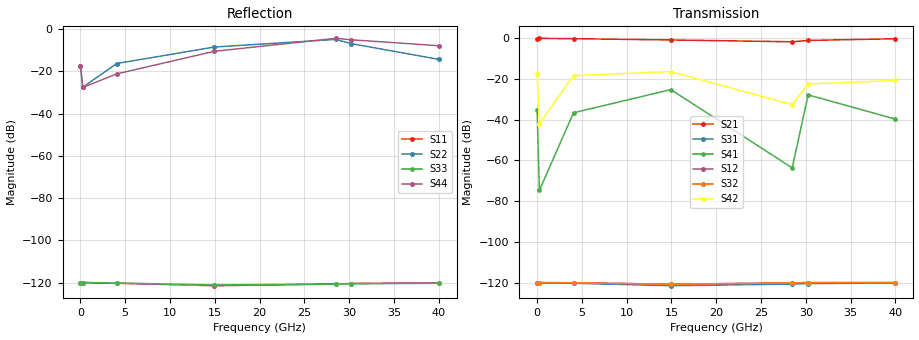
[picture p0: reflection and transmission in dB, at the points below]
# GHz S MA R 50
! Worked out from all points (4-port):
!   4000 points, 5 MHz to 39.99 GHz, reference 50 ohm
!   strongest paths, dB at 5 MHz, 10.01 GHz, 20 GHz, 30 GHz, 39.99 GHz:
!     S21: -0.2, -0.6, -1.2, -1.1, -0.2
!     S43: -0.2, -0.4, -1.1, -1.7, -0.8
!     S42: -17.7, -13.4, -25.6, -24.6, -20.7
!     S23: -35.3, -26.2, -31.6, -28.9, -39.7
!     S41: -35.3, -26.2, -31.6, -28.9, -39.7
!     S32: -120.0, -120.6, -120.7, -119.9, -120.0
!   lowest |S11| = -121.5 dB at 14.93 GHz (marker M1), VSWR 1.00, Z = 50 - j3.09e-06 ohm
!   |S11| at or under -10 dB: start of sweep to end of sweep
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0.005  9.717e-07 0.5  1.002e-06 -0.4  9.718e-07 0.5  1.002e-06 -0.4
       0.9823 0.0  0.1336 124.6  0.01708 179.9  0.1303 110.6
       9.717e-07 0.5  1.002e-06 -0.4  9.718e-07 0.5  1.002e-06 -0.4
       0.01708 -179.9  0.1299 110.2  0.9824 -0.0  0.1328 125.2
0.255  9.99e-07 0.0  1e-06 -0.0  9.99e-07 0.0  1e-06 -0.0
       0.9991 0.0  0.04194 162.0  0.0001843 177.1  0.008002 108.5
       9.99e-07 0.0  1e-06 -0.0  9.99e-07 0.0  1e-06 -0.0
       0.0001843 -177.1  0.008042 109.2  0.9991 -0.0  0.04138 168.8
4.065  9.634e-07 0.4  9.936e-07 -0.4  9.722e-07 0.3  9.952e-07 -0.3
       0.9805 0.0  0.1527 55.9  0.01485 178.3  0.1224 60.4
       9.634e-07 0.4  9.936e-07 -0.4  9.722e-07 0.3  9.952e-07 -0.3
       0.01485 -178.3  0.1222 60.5  0.9886 -0.0  0.08691 57.0
14.925  8.415e-07 -2.1  9.14e-07 2.0  8.743e-07 -1.9  9.336e-07 1.7
        0.913 -0.0  0.3745 -31.7  0.05506 -177.4  0.1521 -32.5
        8.415e-07 -2.1  9.14e-07 2.0  8.743e-07 -1.9  9.336e-07 1.7
        0.05506 177.4  0.1522 -33.2  0.9412 0.0  0.2965 -36.5
28.475  9.213e-07 -4.5  9.841e-07 4.3  9.183e-07 -5.5  9.734e-07 5.1
        0.8232 -0.0  0.5672 -120.2  0.0006589 -108.8  0.02393 -28.6
        9.213e-07 -4.5  9.841e-07 4.3  9.183e-07 -5.5  9.734e-07 5.1
        0.0006589 108.8  0.02358 -31.3  0.7988 0.0  0.6011 -118.2
30.255  9.463e-07 -1.2  1.006e-06 1.1  9.38e-07 -3.0  9.965e-07 2.8
        0.8886 -0.0  0.4505 -126.8  0.04088 -2.9  0.0764 28.9
        9.463e-07 -1.2  1.006e-06 1.1  9.38e-07 -3.0  9.965e-07 2.8
        0.04088 2.9  0.07573 29.2  0.826 0.0  0.557 -126.9
39.995  9.823e-07 -0.1  1.003e-06 -0.2  9.6e-07 0.6  1.018e-06 -0.2
        0.9771 0.0  0.1913 174.9  0.0104 90.2  0.09241 93.1
        9.823e-07 -0.1  1.003e-06 -0.2  9.6e-07 0.6  1.018e-06 -0.2
        0.0104 -90.2  0.09236 92.8  0.9107 -0.0  0.4026 -173.3
